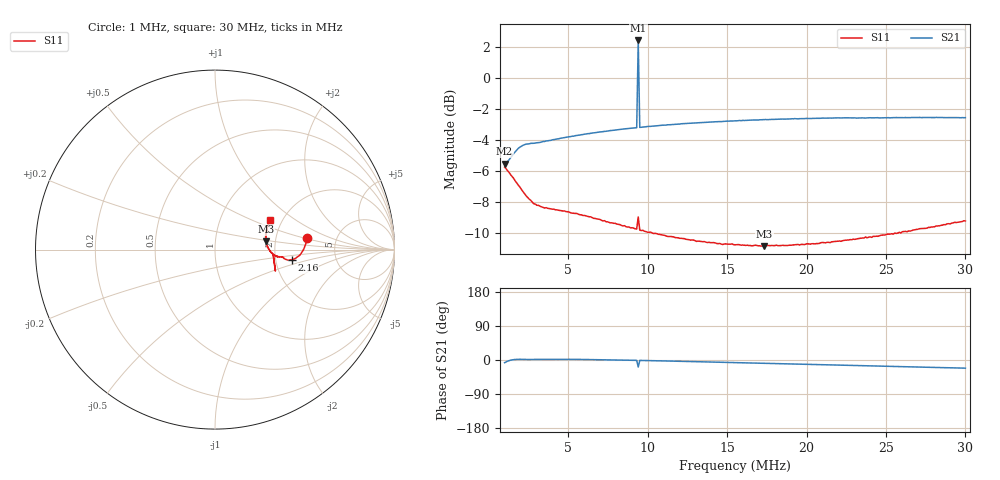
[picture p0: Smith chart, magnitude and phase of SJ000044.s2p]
!File created by NanoVNA-F V2
# Hz S RI R 50
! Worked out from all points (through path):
!   301 points, 1 MHz to 30 MHz, reference 50 ohm
!   highest |S21| = 2.45 dB at 9.41 MHz (marker M1); lowest = -5.5 dB at 1 MHz (marker M2)
!   group delay of S21, straight-line fit = 2.4 ns
!   lowest |S11| = -10.8 dB at 17.34 MHz (marker M3), VSWR 1.81, Z = 89.1 + j8.8 ohm
!   |S11| at or under -10 dB: 10.34 MHz to 25.54 MHz (15.2 MHz wide, 84.7 % of centre); 25.59795 MHz to 25.68438 MHz (86.42 kHz wide, 0.337 % of centre)
!   S12 and S22 are empty: the file has one direction only
!   S11 on the Smith chart (normalised r, x): 1 MHz: 3.04, +0.54; 2.16 MHz: 2.46, -0.34; 30 MHz: 1.73, +0.64
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1000000  0.5131 0.0651  0.5263 -0.0655  0 0  0 0
1193332  0.5023 0.0231  0.5387 -0.0275  0 0  0 0
1483330  0.4812 -0.0195  0.5638 0.00483  0 0  0 0
1676662  0.4644 -0.0373  0.5799 0.0144  0 0  0 0
1869994  0.4493 -0.048  0.5948 0.0189  0 0  0 0
2159992  0.4271 -0.0568  0.6079 0.0174  0 0  0 0
2546656  0.4035 -0.0578  0.6147 0.0137  0 0  0 0
3029986  0.3859 -0.051  0.6193 0.0164  0 0  0 0
3996646  0.3763 -0.041  0.6328 0.0209  0 0  0 0
5833300  0.3605 -0.0392  0.6578 0.017  0 0  0 0
7766620  0.3396 -0.0374  0.679 0.00339  0 0  0 0
9313276  0.3253 -0.0266  0.6931 -0.0113  0 0  0 0
9409942  0.3366 -0.1196  1.256 -0.4237  0 0  0 0
9506608  0.3228 -0.0259  0.6943 -0.0134  0 0  0 0
1.06666e7  0.3134 -0.0162  0.703 -0.0265  0 0  0 0
1.308325e7  0.2976 0.00477  0.7166 -0.0556  0 0  0 0
1.54999e7  0.2889 0.0274  0.7241 -0.0874  0 0  0 0
1.733655e7  0.2837 0.0453  0.7271 -0.1115  0 0  0 0
2.03332e7  0.2826 0.0757  0.7272 -0.152  0 0  0 0
2.216985e7  0.2834 0.0918  0.724 -0.1754  0 0  0 0
2.51665e7  0.2896 0.1216  0.7152 -0.2149  0 0  0 0
2.99998e7  0.3054 0.1638  0.6946 -0.2742  0 0  0 0
